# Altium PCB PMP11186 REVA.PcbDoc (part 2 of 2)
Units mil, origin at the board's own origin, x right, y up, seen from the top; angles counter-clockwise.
Board outline 5750 x 3370 mil, 4 copper layers (Top Layer, Signal Layer 1, Signal Layer 2, Bottom Layer), stack 85.4 mil thick; 92 components, 39 nets, 228 pads, 139 vias.

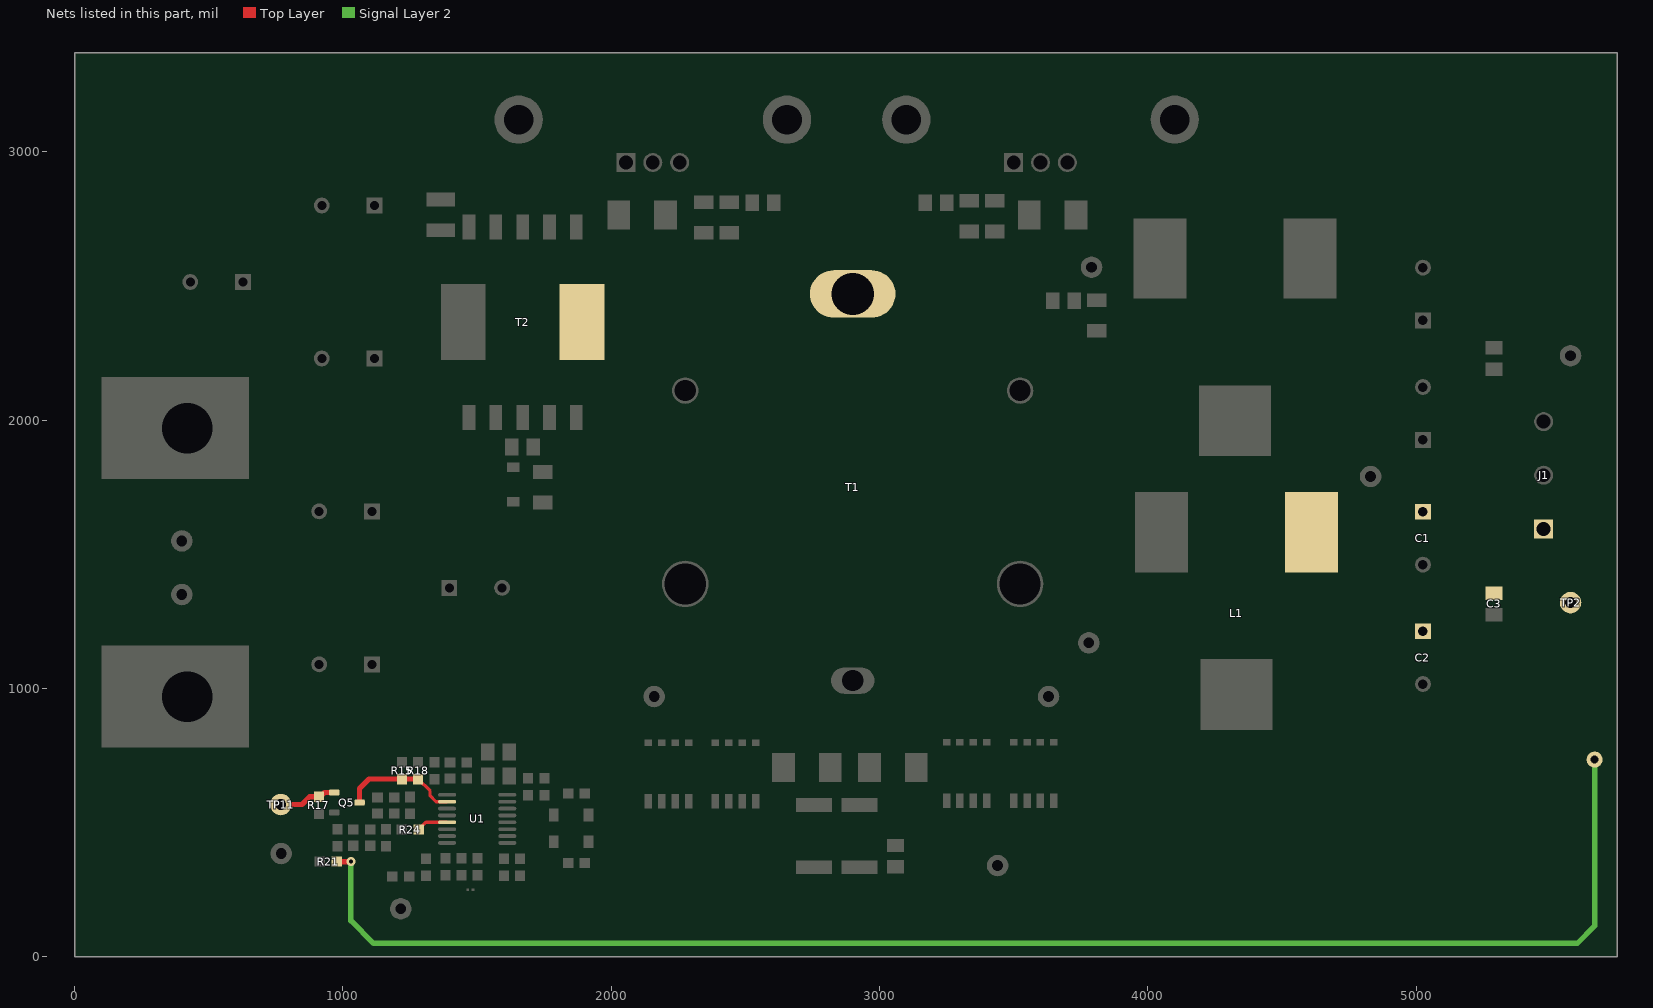
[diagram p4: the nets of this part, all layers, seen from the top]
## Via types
v1: diameter 34, hole 16, Top Layer to Bottom Layer, 83 vias
v2: diameter 32, hole 16, Top Layer to Bottom Layer, 56 vias

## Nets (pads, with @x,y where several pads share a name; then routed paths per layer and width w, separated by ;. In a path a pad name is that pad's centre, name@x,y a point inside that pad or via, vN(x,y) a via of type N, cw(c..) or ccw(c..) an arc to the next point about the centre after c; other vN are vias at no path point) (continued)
NetQ5_1: Q5.1 R17.2 TP11.1 | length 217.7
  Top Layer w20: TP11.1@768.65,567.6 847.6,567.6 876.5,596.5 R17.2@910.89,596.5 916.5,596.5 932.4,612.4 Q5.1@967.76,612.4
NetQ5_3: Q5.3 R15.1 R18.2 U1.2 | length 438.8
  Top Layer w12: R18.2@1280.68,662.52 1325,618.2 1325,600 1347.01,577.99 U1.2@1388.48,577.99
  Top Layer w20: Q5.3@1062.24,575 1062.24,627.24 1097.52,662.52 R18.2@1280.68,662.52
NetR24_2: R24.2 U1.5 | length 117.6
  Top Layer w12: R24.2@1282.18,474.01 1309.38,501.22 U1.5@1388.48,501.22
NetT1_5: T1.5 T2.12
VOUT: C1.1 C2.1 C3.1 J1.1 L1.1 pad.0 R21.1 TP2.1 | length 5590.6
  Top Layer w20: R21.1@976.5,355 v1(1030,355)
  Signal Layer 2 w20: v1(1030,355) 1030,135 1115,50 5600,50 5665,115 pad.0@5665,735
pads on no net: H1.1 H1.2 H2.1 H2.2 L1.3 L2.3 T2.1 T2.3 T2.5 T2.6 T2.7 T2.8 T2.9 T2.10

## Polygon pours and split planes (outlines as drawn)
GND on Top Layer "Top Layer-No Net 10" (solid, remove dead copper, pour order 52): 4.71,3375 5744.71,3375 5749.71,3370 5749.71,0 -0.29,0
VOUT on Top Layer "Top Layer-No Net 9" (solid, remove dead copper, pour order 42): 5750,1705 4805,1705 4745,1765 4350,1765 4350,1710 4350,1240 4405,1185 4420,1170 4450,1170 4470,1170 4545,1095 4550,1090 4550,940 4550,765 4630,685 5750,685
NetC14_2 on Top Layer "Top Layer-No Net" (solid, remove dead copper, pour order 40): 4350,2920 4350,2250 4450,2250 4455,2250 4670,2035 4705,2000 5085,2000 5090,2000 5165,1925 5195,1895 5750,1895 5750,3005 4435,3005
NetD4_1 on Top Layer "Top Layer-No Net 4" (solid, remove dead copper, pour order 36): 3665.05,2711.55 3664.8,2711.8 3664.8,2809.8 3664.8,2824.8 3665,2825 3625,2865 3620,2865 3586.63,2865 3542.06,2909.57 3539.65,2909.57 3539.65,3008.65 3620,3089 3956,3089 4040.95,3004.05 4215.95,3004.05 4300,2920 4300,2251.07 3746.07,2251.07 3745,2250 3745,2710
NetC4_1 on Top Layer "Top Layer-No Net 7" (solid, remove dead copper, pour order 38): 2105,3370 2105,2908.06 2103.06,2908.06 2075,2880 1995,2880 1990,2880 1965,2855 1965,2630 1965,2610 2010,2565 2965,2565 2965,2560 3065,2460 3065,2330 3065,1730.29 3125,1670.29 3744.69,1670.29 3745.85,1669.13 3839.13,1575.85 3839.13,1304.91 3731.96,1197.74 3755,1174.69 3755,1050 4110,1050 4300,1240 4300,1760 4245,1815 4245,1820 4195,1820 4185,1830 4155,1860 4155,1865 4155,1910 3815,2250 3730,2250 3730,2824.68 3540,3014.68 3540,3310 3480,3370
NetT1_5 on Top Layer "Top Layer-No Net 8" (solid, remove dead copper, pour order 30): 1760,2575 1955,2575 1980,2550 2540,2550 3000,2550 3050,2500 3050,2260 3050,2185 3010,2145 1760,2145
NetC17_2 on Top Layer "Top Layer-No Net 5" (solid, remove dead copper, pour order 18): 2775,760 3005,760 3005,616.69 3031.69,590 3035,590 3090,590 3095,585 3095,385 2655,385 2630,410 2630,590 2758.61,590 2775,606.39
NetC6_1 on Top Layer "Top Layer-No Net 6" (solid, remove dead copper, pour order 16): 2650,360 2625,335 2625,280 2650,255 2655,250 3070,250 3100,280 3100,335 3100,360
NetD6_2 on Top Layer "Top Layer-No Net 3" (solid, remove dead copper, pour order 10): 3035,625 3035,1565 3125,1655 3570,1655 3740,1655 3825,1570 3825,990 3825,720 3730,625
NetD5_2 on Top Layer "Top Layer-No Net 2" (solid, remove dead copper, pour order 8): 2745,980 2745,1560 2745,1570 2660,1655 2105,1655 2010,1655 1920,1565 1920,1005 1920,740 2025,635 2033.22,626.78 2745,626.78
NetC6_1 on Top Layer "Top Layer-No Net 1" (solid, remove dead copper, pour order 4): 0,1460 620,1460 955,1125 955,1020 1015,960 1435,960 1520,1045 1520,1850 1430,1940 1430,2085.47 1580.47,2085.47 1640,2145 1640,2575 1570.48,2644.52 1570,2644.52 1420.48,2644.52 1420.47,2644.53 1420.33,2644.67 1420.33,2781.5 1295.56,2781.5 1296.85,2781.5 1296.85,2863.15 1065,3095 635,3095 0,3095
GND on Bottom Layer "Bottom Layer-No Net" (solid, remove dead copper, pour order 46): 0,3370 5750,3370 5750,0 5745,-5 -5,-5
NetD1_3 on Bottom Layer "Bottom Layer-No Net 1" (solid, remove dead copper, pour order 22): 2075,2065 2045,2095 2045,2760 2205,2920 2205,3370 3795,3370 3790,3365 3790,2520 3685,2415 3230,1960 3055,1960 2180,1960
GND on Signal Layer 2 "Signal Layer 2-No Net 2" (solid, remove dead copper, pour order 48): 0,3370 5750,3370 5750,0 5,0 0,5
NetC6_1 on Signal Layer 2 "Signal Layer 2-No Net 1" (solid, remove dead copper, pour order 44): 2625,335 2625,280 2655,250 3050,250 3070,250 3090,270 3090,510 3090,590 2470,1210 1605,1210 1485,1210 1455,1180 1455,1060 1455,1040 1485,1010 1640,855 1670,825 2225,825 2440,825 2625,640
NetD1_1 on Signal Layer 2 "Signal Layer 2-No Net" (solid, remove dead copper, pour order 24): 3615,1960 3730,2075 3730,2460 3787.64,2517.64 3790,2520 3790,3370 1945,3370 1950,3365 1950,2780 1950,2430 2130,2250 2195,2185 2320,2185 2325,2185 2485,2025 2550,1960 2670,1960
GND on Signal Layer 1 "Signal Layer 1-No Net" (solid, remove dead copper, pour order 50): 0,3370 5750,3370 5750,0 5745,5 10,5

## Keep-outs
Keep-Out Layer:
  the board outline again, w7
  text ".Layer_Name" at 577,-858.49 h60

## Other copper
Top Layer:
  text ".Layer_Name" at 577,-858.49 h60
Bottom Layer:
  text ".Layer_Name" at 577,-858.49 h60

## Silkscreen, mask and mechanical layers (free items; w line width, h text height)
Top Overlay:
  text "-VOUT" at 5710,1920 h40 r90
  text "GND" at 5710,1730 h40 r90
  text "VIN" at 100,1665 h40
  text "+VOUT" at 5710,1435 h40 r90
  text "GND" at 100,1215 h40
  text ".PRJ_Number" at 4930,80 h60
  text ".PCB_Rev" at 5530,80 h60
  text ".Layer_Name" at 577,-858.49 h60
Bottom Overlay:
  text ".Layer_Name" at 577,-858.49 h60
Top Paste:
  text ".Layer_Name" at 577,-858.49 h60
Bottom Paste:
  text ".Layer_Name" at 577,-858.49 h60
Top Solder:
  text ".Layer_Name" at 577,-858.49 h60
  text ".Layer_Name" at 577,-858.49 h60
Bottom Solder:
  text ".Layer_Name" at 577,-858.49 h60
Drill Guide:
  text ".Layer_Name" at 577,-858.49 h60
M1 Board Outline:
  lines w7: 0,0 0,3370 5750,3370 5750,0 0,0
  lines w10: 0,0 0,3370 5750,3370 5750,0 0,0
  text ".Layer_Name" at 577,-858.49 h60
M2 Board Dimensions:
  rectangle: 0,-275 125,-150
  rectangle: 125,-400 500,-275
  lines w7: 0,-275 1000,-275 ; 125,-400 125,-150 ; 250,-400 250,-150 ; 500,-400 500,-150 ; 750,-400 750,-150 ; 0,-400 1000,-400 1000,-150 0,-150 0,-400
  text ".Layer_Name" at 577,-858.49 h60
M3 3D STEP Top:
  text ".Layer_Name" at 577,-858.49 h60
M4 3D STEP Bottom:
  text ".Layer_Name" at 577,-858.49 h60
M5 Assembly Top:
  circle w5: c5025,1115 r195.06
  circle w5: c5025,1560 r195.06
  circle w5: c5025,2025 r195.06
  circle w5: c5025,2465 r195.06
  lines w10: -292,-930.17 6308,-930.17 ; -292,-726.83 6310,-726.83 ; -292,-523.5 -292,-1133.5 3713,-1133.5 6310,-1133.5 6310,-523.5 -291.5,-523.5 -291.5,-1133.5 1284,-1133.5 ; 2173,-1133.5 2173,-523.5 ; 3440,-726.83 3440,-523.5 ; 4280,-726.83 4280,-523.5 ; 4902,-1140 4902,-937.17 ; 5075,1215 5125,1215 ; 5075,1655 5125,1655 ; 5075,1925 5125,1925 ; 5075,2370 5125,2370 ; 5100,1190 5100,1240 ; 5100,1630 5100,1680 ; 5100,1900 5100,1950 ; 5100,2345 5100,2395
  text "COMPONENTS MARKED 'DNP' SHOULD NOT BE POPULATED." at 1153.5,-318.5 h60
  text "ASSEMBLY VARIANT:" at 1153,-434 h60
  text ".VariantName" at 2189,-434 h60
  text "PCB VIEWED FROM TOP SIDE" at -228.5,-655.67 h60
  text "BOARD #:" at 2248,-655.67 h60
  text ".PRJ_Number" at 2793.5,-655.67 h60
  text "REV:" at 3638,-655.67 h60
  text ".PCB_Rev" at 3929.5,-655.67 h60
  text "SVN REV:" at 4476,-655.67 h60
  text ".VersionControl_RevNumber" at 4982,-655.67 h60
  text "TID #:" at 2248,-859 h60
  text ".TID" at 2793.5,-859 h60
  text "PLOT NAME =" at -228.5,-1064.34 h60
  text ".plot_File_Name" at 577,-1064.34 h60
  text "GENERATED    :" at 2250,-1064.34 h60
  text ".Print_Date" at 3119.5,-1064.34 h60
  text ".Print_Time" at 3848.5,-1064.34 h60
  text "TEXAS INSTRUMENTS" at 5113,-1064.34 h60
M6 Assembly Bottom:
  lines w10: -292.5,-727.33 6309.5,-727.33 ; -290.5,-930.67 6309.5,-930.67 ; 1115.5,-1140.5 1115.5,-937.67 ; 1737.5,-727.33 1737.5,-524 ; 2577.5,-727.33 2577.5,-524 ; 3844.5,-1134 3844.5,-524 ; 4733.5,-1134 6309,-1134 6309,-524 -292.5,-524 -292.5,-1134 2304.5,-1134 6309.5,-1134 6309.5,-524
  text "COMPONENTS MARKED 'DNP' SHOULD NOT BE POPULATED." at 6102,-318 h60
  text ".VariantName" at 5058,-434 h60
  text "ASSEMBLY VARIANT:" at 6097,-434 h60
  text ".VersionControl_RevNumber" at 1035.5,-656.17 h60
  text "SVN REV:" at 1541.5,-656.17 h60
  text ".PCB_Rev" at 2088,-656.17 h60
  text "REV:" at 2379.5,-656.17 h60
  text ".PRJ_Number" at 3224,-656.17 h60
  text "BOARD #:" at 3769.5,-656.17 h60
  text "PCB VIEWED FROM BOTTOM SIDE" at 6246,-656.17 h60
  text ".TID" at 3224,-859.5 h60
  text "TID #:" at 3769.5,-859.5 h60
  text "TEXAS INSTRUMENTS" at 904.5,-1064.84 h60
  text ".Print_Time" at 2169,-1064.84 h60
  text ".Print_Date" at 2898,-1064.84 h60
  text "GENERATED    :" at 3767.5,-1064.84 h60
  text ".plot_File_Name" at 5440.5,-1064.84 h60
  text "PLOT NAME =" at 6246,-1064.84 h60
M9 Title Sheet:
  drawing of 57 lines, arcs and shapes, not listed
  text "1" at 739.84,8036.5 h70
  text "2" at 3235.5,8036.5 h70
  text "3" at 5724.84,8036.5 h70
  text "4" at 8231.51,8036.5 h70
  text "5" at 10730.5,8036.5 h70
  text "6" at 13235.5,8036.5 h70
  text "A" at -416.5,6893.5 h70
  text "A" at 14383.5,6893.5 h70
  text "B" at -416.5,4513.5 h70
  text "B" at 14383.5,4513.5 h70
  text "C" at -416.5,2138.5 h70
  text "C" at 14383.5,2138.5 h70
  text "PROJECT TITLE:" at 11343.5,277.5 h45
  text ".PRJ_Title" at 11393.5,144.17 h70
  text "DESIGNED FOR:" at 11343.5,-23.5 h45
  text ".PRJ_Customer" at 11393.5,-163.5 h70
  text "D" at -416.5,-231.5 h70
  text "D" at 14383.5,-231.5 h70
  text "FILE NAME:" at 11343.5,-323.5 h45
  text ".PCB_File_Name_No_Path" at 11393.5,-443.5 h70
  text "Texas Instruments (TI) and/or its licensors do not warrant the accuracy or completeness of this specification" at 6374,-605.34 h45
  text "ENGINEER:" at 11343.5,-613.5 h45
  text "LAYOUT BY:" at 12848.5,-613.5 h45
  text "or any information contained therein. TI and/or its licensors do not warrant that this design will meet" at 6329.01,-718 h45
  text ".PRJ_Engineer" at 11393.5,-768.49 h70
  text ".PCB_Layout" at 12899,-768.49 h70
  text "the specifications, will be suitable for your application or fit for any particular purpose, or will operate in" at 6329.01,-830.67 h45
  text ".Layer_Name" at 577,-858.49 h60
  text "ALTIUM DESIGNER VERSION:" at 12848.5,-923.5 h45
  text "an implementation. TI and/or its licensors do not warrant that the design is production worthy. You should" at 6329.01,-943.33 h45
  text "completely validate and test your design implementation to confirm the system functionality for your application." at 6374,-1056 h45
  text ".print_Scale" at 11393.5,-1056.83 h70
  text ".Application_BuildNumber" at 12899,-1056.83 h70
  text "1" at 739.84,-1263.5 h70
  text "2" at 3235.5,-1263.5 h70
  text "3" at 5724.84,-1263.5 h70
  text "4" at 8231.51,-1263.5 h70
  text "5" at 10730.5,-1263.5 h70
  text "6" at 13235.5,-1263.5 h70
M10 Fab Notes:
  drawing of 185 lines, arcs and shapes, not listed
  text "DESIGN INFORMATION" at 12381.02,5910 h60
  text "MIN. TRACK WIDTH:" at 11736.46,5730 h60
  text "8" at 12832.7,5730 h60
  text "MIL" at 12987.46,5730 h60
  text "MIN. CLEARANCE:" at 11736.46,5598 h60
  text "0.2" at 12772.7,5598 h60
  text "mm" at 12987.46,5598 h60
  text "MIN. VIA PAD SIZE:" at 11736.46,5466 h60
  text "24" at 12802.71,5466 h60
  text "MIL" at 12987.46,5466 h60
  text "0.05mm (2MIL)" at 12431.46,5324.29 h60
  text "MINIMUM ANNULAR RING" at 11407.23,5320 h60
  text "EXTERNAL" at 13139.46,5320 h60
  text "PER" at 11607.23,5202 h60
  text "IPC-D-275 CLASS 2 LEVEL C" at 11827.23,5202 h60
  text "MIL, HOLES" at 13315.46,5089.71 h60
  text "+/-" at 12923,5089 h60
  text "+/-" at 13777,5089 h60
  text "REGISTRATION TOLERANCES:" at 11407.23,5084 h60
  text "METAL" at 12607,5084 h60
  text "5" at 13183.2,5084 h60
  text "3" at 14016.2,5084 h60
  text "MIL" at 14132.46,5084 h60
  text "MATERIAL:" at 11332.46,4874.54 h60
  text "FR-4 High Tg" at 12318.9,4734.21 h60
  text "FR-408" at 11753.46,4725.64 h60
  text "X" at 12165.46,4725.64 h60
  text "OTHER" at 13241.46,4725.64 h60
  text "62 MIL (1.6mm) +/-10%" at 12073.56,4562.92 h60
  text "THICKNESS:" at 11407.23,4558.64 h60
  text "X" at 11945.4,4558.64 h60
  text "OTHER" at 13358.46,4558.64 h60
  text "TOLERANCE:" at 11407.23,4400.64 h60
  text "X" at 12246.53,4400.64 h60
  text "ANSI IPC-6012 TYPE 3 CLASS 2" at 12433.48,4400.64 h60
  text "OTHER +/-" at 12433.46,4244.64 h60
  text "BOW & TWIST:" at 11407.23,4087.64 h60
  text "X" at 12246.53,4087.64 h60
  text "ANSI IPC-6012 TYPE 3 CLASS 2" at 12433.48,4087.64 h60
  text "OTHER +/-" at 12433.46,3929.13 h60
  text "DRILLING:" at 11332.46,3790.64 h60
  text "REFERENCE:" at 11407.23,3673.64 h60
  text "X" at 12055.46,3673.64 h60
  text "AS SHOWN" at 12242.46,3673.64 h60
  text "X" at 12956.46,3673.64 h60
  text "NC_DRILL FILES" at 13093.46,3673.64 h60
  text "PTH MIN COPPER THICKNESS:" at 11407.23,3515.64 h60
  text "X" at 12757.46,3515.64 h60
  text "1MIL" at 12894.46,3515.64 h60
  text "OTHER" at 13391.46,3515.64 h60
  text "BOARD FINISH:" at 11332.46,3356.64 h60
  text "SILKSCREEN:" at 11487.68,3238.64 h60
  text "X" at 12436.46,3238.64 h60
  text "TOP" at 12562.46,3238.64 h60
  text "X" at 12946.46,3238.64 h60
  text "BOTTOM" at 13073.46,3238.64 h60
  text "SILKSCREEN COLOR:" at 11487.68,3071.64 h60
  text "X" at 12435.42,3071.64 h60
  text "WHITE" at 12562.46,3071.64 h60
  text "OTHER" at 13073.46,3071.64 h60
  text "SOLDER RESIST COLOR:" at 11487.68,2901.64 h60
  text "X" at 12650,2755 h60
  text "GREEN" at 12182.46,2742.44 h60
  text "BLUE" at 12773.46,2742.44 h60
  text "OTHER" at 13311.46,2742.44 h60
  text "IMMERSION GOLD (ENIG)" at 12393.46,2553.92 h60
  text "ENEPIG" at 13731,2550.64 h60
  text "SURFACE FINISH:" at 11332.46,2549.64 h60
  text "IMM. TIN/SILVER OR EQUIV" at 11662,2392.64 h60
  text "OTHER" at 13093.46,2392.64 h60
  text "X" at 11500,2390 h60
  text "ARRAY/PANEL:" at 11332.46,2213.64 h60
  text "CUT AND TRIM PER MECH LAYER 1" at 12393.46,2209.35 h60
  text "N.C. ROUTE" at 12393.46,2057.64 h60
  text "X" at 13072.46,2057.64 h60
  text "V. SCORE" at 13259.46,2057.64 h60
  text "CERTIFICATION:" at 11332.46,1920.64 h60
  text "MATERIALS AND WORKMANSHIP FOR ALL PCBS" at 12057.46,1920.64 h60
  text "TO MEET OR EXCEED THE REQUIREMENTS OF:" at 12057.46,1822.64 h60
  text "X" at 11683.96,1686.13 h60
  text "ANSI IPC-A-600F CLASS ->" at 11822.96,1686.13 h60
  text "X" at 13462.02,1686.13 h60
  text "2" at 13580.96,1686.14 h60
  text "1" at 13265.96,1684.64 h60
  text "3" at 13934.96,1684.64 h60
  text "X" at 11686.02,1526.64 h60
  text "UL 94V-0" at 11822.96,1526.64 h60
  text "X" at 12498.02,1526.64 h60
  text "RoHS" at 12634.96,1526.64 h60
  text "OTHER" at 13279.36,1526.64 h60
  text "PER ORDER" at 13676.42,1526.64 h60
  text "ADDITIONAL REQUIREMENTS:" at 11332.46,1385.64 h60
  text "MICROSECTION:" at 11407.23,1270.64 h60
  text "YES" at 12312.96,1270.64 h60
  text "REQUIRED" at 13174.46,1114.49 h60
  text "BARE BOARD ELEC. TEST:" at 11407.23,1111.64 h60
  text "NONE" at 12712.96,1111.64 h60
  text "X" at 13047.46,1111.64 h60
  text "PER ORDER" at 13766.46,1111.64 h60
  text "MANUFACTURER'S UL:" at 11407.23,954.64 h60
  text "RAIL" at 12572.96,950.35 h60
  text "METAL" at 13064.77,950.35 h60
  text "X" at 13440,950 h60
  text "SILK" at 13576.46,950.35 h60
  text ".Layer_Name" at 577,-858.49 h60
M11 Gerber Information:
  lines w10: -292,-930.17 6308,-930.17 ; -292,-726.83 6310,-726.83 ; -292,-523.5 -292,-1133.5 3713,-1133.5 6310,-1133.5 6310,-523.5 -291.5,-523.5 -291.5,-1133.5 1284,-1133.5 ; 2173,-1133.5 2173,-523.5 ; 3440,-726.83 3440,-523.5 ; 4280,-726.83 4280,-523.5 ; 4902,-1140 4902,-937.17
  text "ALL ARTWORK VIEWED FROM TOP SIDE" at -228.5,-655.67 h60
  text "BOARD #:" at 2248,-655.67 h60
  text ".PRJ_Number" at 2793.5,-655.67 h60
  text "REV:" at 3638,-655.67 h60
  text ".PCB_Rev" at 3929.5,-655.67 h60
  text "SVN REV:" at 4476,-655.67 h60
  text ".VersionControl_RevNumber" at 4982,-655.67 h60
  text "LAYER NAME =" at -228.5,-858.49 h60
  text "TID #:" at 2248,-859 h60
  text ".TID" at 2793.5,-859 h60
  text "PLOT NAME =" at -228.5,-1064.34 h60
  text ".plot_File_Name" at 577,-1064.34 h60
  text "GENERATED    :" at 2250,-1064.34 h60
  text ".Print_Date" at 3119.5,-1064.34 h60
  text ".Print_Time" at 3848.5,-1064.34 h60
  text "TEXAS INSTRUMENTS" at 5113,-1064.34 h60
M12 Stackup:
  drawing of 295 lines, arcs and shapes, not listed
  text "Layer" at 9780.35,7840 h60
  text "Name" at 10190.26,7840 h60
  text "Material" at 11130,7840 h60
  text "Thickness" at 11989.77,7840 h60
  text "Constant" at 12639.6,7840 h60
  text "Board Layer Stack" at 13209.46,7840 h60
  text "1" at 9780.35,7720 h60
  text "Top Overlay" at 10190.26,7720 h60
  text "2" at 9780.35,7600 h60
  text "Top Solder" at 10190.26,7600 h60
  text "Solder Resist" at 11130,7600 h60
  text "0.40mil" at 11989.77,7600 h60
  text "3.5" at 12639.6,7600 h60
  text "3" at 9780.35,7480 h60
  text "Top Layer" at 10190.26,7480 h60
  text "Copper" at 11130,7480 h60
  text "2.80mil" at 11989.77,7480 h60
  text "4" at 9780.35,7360 h60
  text "Dielectric1" at 10190.26,7360 h60
  text "FR-4" at 11130,7360 h60
  text "59.20mil" at 11989.77,7360 h60
  text "4.8" at 12639.6,7360 h60
  text "5" at 9780.35,7240 h60
  text "Signal Layer 1" at 10190.26,7240 h60
  text "Copper" at 11130,7240 h60
  text "2.80mil" at 11989.77,7240 h60
  text "6" at 9780.35,7120 h60
  text "Dielectric 3" at 10190.26,7120 h60
  text "5.00mil" at 11989.77,7120 h60
  text "4.2" at 12639.6,7120 h60
  text "7" at 9780.35,7000 h60
  text "Signal Layer 2" at 10190.26,7000 h60
  text "Copper" at 11130,7000 h60
  text "2.80mil" at 11989.77,7000 h60
  text "8" at 9780.35,6880 h60
  text "Dielectric 2" at 10190.26,6880 h60
  text "10.00mil" at 11989.77,6880 h60
  text "4.2" at 12639.6,6880 h60
  text "9" at 9780.35,6760 h60
  text "Bottom Layer" at 10190.26,6760 h60
  text "Copper" at 11130,6760 h60
  text "2.80mil" at 11989.77,6760 h60
  text "10" at 9780.35,6640 h60
  text "Bottom Solder" at 10190.26,6640 h60
  text "Solder Resist" at 11130,6640 h60
  text "0.40mil" at 11989.77,6640 h60
  text "3.5" at 12639.6,6640 h60
  text "11" at 9780.35,6520 h60
  text "Bottom Overlay" at 10190.26,6520 h60
  text ".Layer_Name" at 577,-858.49 h60
M13 Component Bodies Top:
  text ".Layer_Name" at 577,-858.49 h60
M14 Component Bodies Bottom:
  text ".Layer_Name" at 577,-858.49 h60
M15 Courtyards Top:
  text ".Layer_Name" at 577,-858.49 h60
M16 Courtyards Bottom:
  text ".Layer_Name" at 577,-858.49 h60
Drill Drawing:
  circle w3.33: c7766.73,5726.81 r18.09
  circle w3.33: c7766.73,5726.81 r30.15
  circle w3.33: c7766.73,5365.01 r30.15
  lines w3.33: 7736.58,3706.72 7796.88,3706.72 7796.88,3767.02 7736.58,3767.02 7736.58,3706.72 ; 7736.58,3917.77 7766.73,3887.62 7796.88,3917.77 7766.73,3947.93 7736.58,3917.77 ; 7736.58,4083.6 7751.66,4083.6 7766.73,4068.53 7781.81,4083.6 7796.88,4083.6 7781.81,4098.68 7796.88,4113.75 7781.81,4113.75 7766.73,4128.83 7751.66,4113.75 7736.58,4113.75 7751.66,4098.68 7736.58,4083.6 ; 7736.58,4249.43 7736.58,4264.51 7751.66,4279.58 7736.58,4294.66 7736.58,4309.73 7751.66,4309.73 7766.73,4294.66 7781.81,4309.73 7796.88,4309.73 7796.88,4294.66 7781.81,4279.58 7796.88,4264.51 7796.88,4249.43 7781.81,4249.43 7766.73,4264.51 7751.66,4249.43 7736.58,4249.43 ; 7736.58,4445.41 7751.66,4445.41 7751.66,4430.34 7781.81,4430.34 7781.81,4445.41 7796.88,4445.41 7796.88,4475.56 7781.81,4475.56 7781.81,4490.64 7751.66,4490.64 7751.66,4475.56 7736.58,4475.56 7736.58,4445.41 ; 7736.58,4611.24 7766.73,4626.32 7796.88,4611.24 7781.81,4641.39 7796.88,4671.54 7766.73,4656.47 7736.58,4671.54 7751.66,4641.39 7736.58,4611.24 ; 7736.58,4807.22 7751.66,4807.22 7766.73,4792.14 7781.81,4807.22 7796.88,4807.22 7781.81,4822.29 7796.88,4837.37 7781.81,4837.37 7766.73,4852.45 7751.66,4837.37 7736.58,4837.37 7751.66,4822.29 7736.58,4807.22 ; 7736.58,5033.35 7796.88,5033.35 7766.73,4973.05 7736.58,5033.35 ; 7736.58,5214.25 7796.88,5214.25 7766.73,5153.95 7736.58,5214.25 ; 7736.58,5515.76 7796.88,5515.76 7796.88,5576.06 7736.58,5576.06 7736.58,5515.76 ; 7748.64,3718.78 7784.82,3718.78 7784.82,3754.96 7748.64,3754.96 7748.64,3718.78 ; 7748.64,4089.63 7757.69,4089.63 7766.73,4080.59 7775.78,4089.63 7784.82,4089.63 7775.78,4098.68 7784.82,4107.72 7775.78,4107.72 7766.73,4116.77 7757.69,4107.72 7748.64,4107.72 7757.69,4098.68 7748.64,4089.63 ; 7748.64,5021.29 7784.82,5021.29 7766.73,4985.11 7748.64,5021.29
  lines w12: 7655.06,3652.45 10275.15,3652.45 ; 7655.06,5823.3 10275.15,5823.3 ; 8111.19,3471.55 8111.19,6004.2 ; 8552.46,3471.55 8552.46,6004.2 ; 9375.58,3471.55 9375.58,6004.2 ; 9725.5,3471.55 9725.5,6004.2 ; 7655.06,3471.55 10275.15,3471.55 10275.15,6004.2 7655.06,6004.2 7655.06,3471.55
  text "Symbol" at 7763.61,5877.57 h90.26
  text "Quantity" at 8165.46,5877.57 h90.26
  text "Finished Hole Size" at 8606.73,5877.57 h90.26
  text "Plated" at 9429.85,5877.57 h90.26
  text "Hole Type" at 9779.77,5877.57 h90.26
  text "139" at 8165.46,5696.66 h75.21
  text "16.00mil (0.406mm)" at 8606.73,5696.66 h75.21
  text "PTH" at 9429.85,5696.66 h75.21
  text "Round" at 9779.77,5696.66 h75.21
  text "1" at 8165.46,5515.76 h75.21
  text "30.00mil (0.762mm)" at 8606.73,5515.76 h75.21
  text "PTH" at 9429.85,5515.76 h75.21
  text "Round" at 9779.77,5515.76 h75.21
  text "12" at 8165.46,5334.86 h75.21
  text "33.46mil (0.850mm)" at 8606.73,5334.86 h75.21
  text "PTH" at 9429.85,5334.86 h75.21
  text "Round" at 9779.77,5334.86 h75.21
  text "8" at 8165.46,5153.95 h75.21
  text "35.43mil (0.900mm)" at 8606.73,5153.95 h75.21
  text "PTH" at 9429.85,5153.95 h75.21
  text "Round" at 9779.77,5153.95 h75.21
  text "13" at 8165.46,4973.05 h75.21
  text "40.00mil (1.016mm)" at 8606.73,4973.05 h75.21
  text "PTH" at 9429.85,4973.05 h75.21
  text "Round" at 9779.77,4973.05 h75.21
  text "9" at 8165.46,4792.14 h75.21
  text "51.18mil (1.300mm)" at 8606.73,4792.14 h75.21
  text "PTH" at 9429.85,4792.14 h75.21
  text "Round" at 9779.77,4792.14 h75.21
  text "2" at 8165.46,4611.24 h75.21
  text "78.74mil (2.000mm)" at 8606.73,4611.24 h75.21
  text "PTH" at 9429.85,4611.24 h75.21
  text "Round" at 9779.77,4611.24 h75.21
  text "4" at 8165.46,4430.34 h75.21
  text "110.24mil (2.800mm)" at 8606.73,4430.34 h75.21
  text "PTH" at 9429.85,4430.34 h75.21
  text "Round" at 9779.77,4430.34 h75.21
  text "2" at 8165.46,4249.43 h75.21
  text "153.54mil (3.900mm)" at 8606.73,4249.43 h75.21
  text "PTH" at 9429.85,4249.43 h75.21
  text "Round" at 9779.77,4249.43 h75.21
  text "2" at 8165.46,4068.53 h75.21
  text "188.00mil (4.775mm)" at 8606.73,4068.53 h75.21
  text "PTH" at 9429.85,4068.53 h75.21
  text "Round" at 9779.77,4068.53 h75.21
  text "1" at 8165.46,3887.62 h75.21
  text "78.74mil (2.000mm)" at 8606.73,3887.62 h75.21
  text "PTH" at 9429.85,3887.62 h75.21
  text "Slot" at 9779.77,3887.62 h75.21
  text "1" at 8165.46,3706.72 h75.21
  text "157.48mil (4.000mm)" at 8606.73,3706.72 h75.21
  text "PTH" at 9429.85,3706.72 h75.21
  text "Slot" at 9779.77,3706.72 h75.21
  text "194 Total" at 8165.46,3525.82 h75.21
  text ".Layer_Name" at 577,-858.49 h60

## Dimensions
0,-400 to 1000,-400 on M2 Board Dimensions
0,0 to 0,3370 on M2 Board Dimensions
0,0 to 5750,0 on M2 Board Dimensions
